VERSION 5.7 ;
  NOWIREEXTENSIONATPIN ON ;
  DIVIDERCHAR "/" ;
  BUSBITCHARS "[]" ;
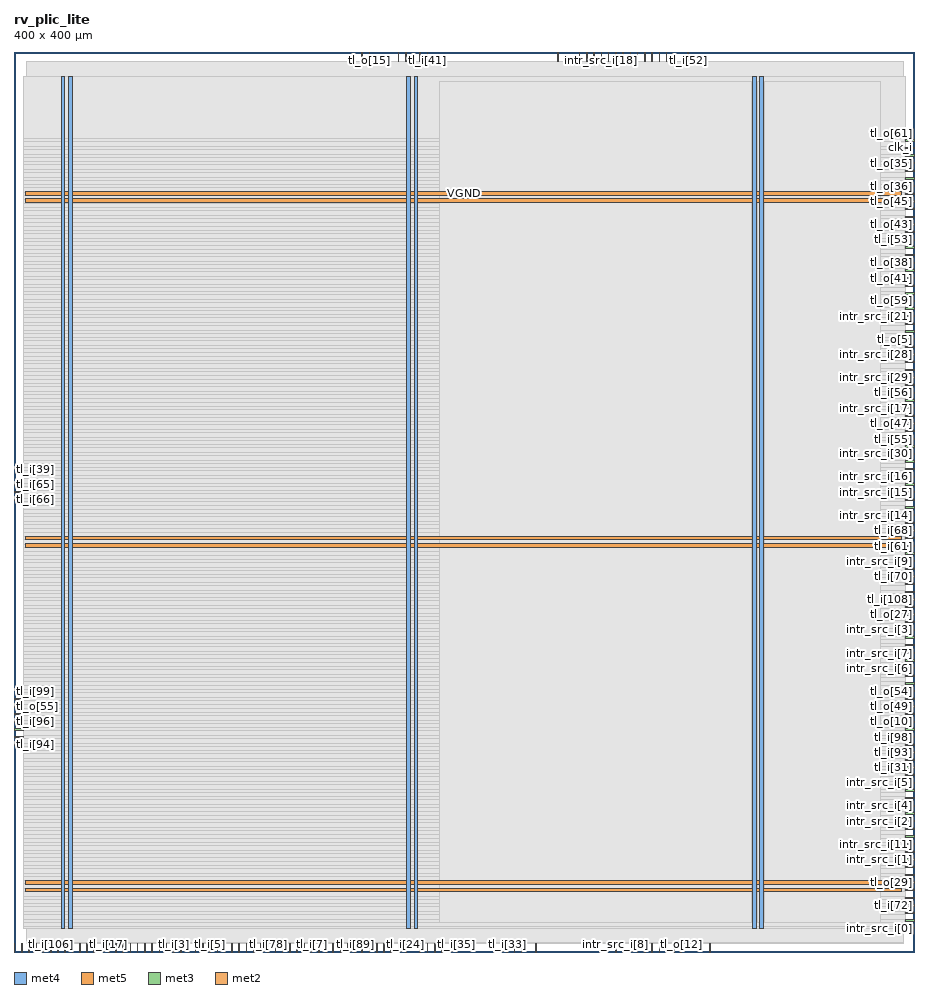
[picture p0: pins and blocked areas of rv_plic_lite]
MACRO rv_plic_lite
  CLASS BLOCK ;
  FOREIGN rv_plic_lite ;
  ORIGIN 0.000 0.000 ;
  SIZE 400.000 BY 400.000 ;
  PIN VGND
    DIRECTION INOUT ;
    USE GROUND ;
    PORT
      LAYER met4 ;
        RECT 24.340 10.640 25.940 389.200 ;
    END
    PORT
      LAYER met4 ;
        RECT 177.940 10.640 179.540 389.200 ;
    END
    PORT
      LAYER met4 ;
        RECT 331.540 10.640 333.140 389.200 ;
    END
    PORT
      LAYER met5 ;
        RECT 5.280 30.030 394.460 31.630 ;
    END
    PORT
      LAYER met5 ;
        RECT 5.280 183.210 394.460 184.810 ;
    END
    PORT
      LAYER met5 ;
        RECT 5.280 336.390 394.460 337.990 ;
    END
  END VGND
  PIN VPWR
    DIRECTION INOUT ;
    USE POWER ;
    PORT
      LAYER met4 ;
        RECT 21.040 10.640 22.640 389.200 ;
    END
    PORT
      LAYER met4 ;
        RECT 174.640 10.640 176.240 389.200 ;
    END
    PORT
      LAYER met4 ;
        RECT 328.240 10.640 329.840 389.200 ;
    END
    PORT
      LAYER met5 ;
        RECT 5.280 26.730 394.460 28.330 ;
    END
    PORT
      LAYER met5 ;
        RECT 5.280 179.910 394.460 181.510 ;
    END
    PORT
      LAYER met5 ;
        RECT 5.280 333.090 394.460 334.690 ;
    END
  END VPWR
  PIN clk_i
    DIRECTION INPUT ;
    USE SIGNAL ;
    ANTENNAGATEAREA 1.286700 ;
    ANTENNADIFFAREA 0.434700 ;
    PORT
      LAYER met3 ;
        RECT 396.000 357.040 400.000 357.640 ;
    END
  END clk_i
  PIN intr_src_i[0]
    DIRECTION INPUT ;
    USE SIGNAL ;
    ANTENNAGATEAREA 0.682200 ;
    ANTENNADIFFAREA 0.434700 ;
    PORT
      LAYER met3 ;
        RECT 396.000 10.240 400.000 10.840 ;
    END
  END intr_src_i[0]
  PIN intr_src_i[10]
    DIRECTION INPUT ;
    USE SIGNAL ;
    ANTENNAGATEAREA 0.631200 ;
    ANTENNADIFFAREA 0.434700 ;
    PORT
      LAYER met3 ;
        RECT 396.000 61.240 400.000 61.840 ;
    END
  END intr_src_i[10]
  PIN intr_src_i[11]
    DIRECTION INPUT ;
    USE SIGNAL ;
    ANTENNAGATEAREA 0.631200 ;
    ANTENNADIFFAREA 0.434700 ;
    PORT
      LAYER met3 ;
        RECT 396.000 44.240 400.000 44.840 ;
    END
  END intr_src_i[11]
  PIN intr_src_i[12]
    DIRECTION INPUT ;
    USE SIGNAL ;
    ANTENNAGATEAREA 0.631200 ;
    ANTENNADIFFAREA 0.434700 ;
    PORT
      LAYER met3 ;
        RECT 396.000 166.640 400.000 167.240 ;
    END
  END intr_src_i[12]
  PIN intr_src_i[13]
    DIRECTION INPUT ;
    USE SIGNAL ;
    ANTENNAGATEAREA 0.631200 ;
    ANTENNADIFFAREA 0.434700 ;
    PORT
      LAYER met3 ;
        RECT 396.000 183.640 400.000 184.240 ;
    END
  END intr_src_i[13]
  PIN intr_src_i[14]
    DIRECTION INPUT ;
    USE SIGNAL ;
    ANTENNAGATEAREA 0.631200 ;
    ANTENNADIFFAREA 0.434700 ;
    PORT
      LAYER met3 ;
        RECT 396.000 193.840 400.000 194.440 ;
    END
  END intr_src_i[14]
  PIN intr_src_i[15]
    DIRECTION INPUT ;
    USE SIGNAL ;
    ANTENNAGATEAREA 0.631200 ;
    ANTENNADIFFAREA 0.434700 ;
    PORT
      LAYER met3 ;
        RECT 396.000 204.040 400.000 204.640 ;
    END
  END intr_src_i[15]
  PIN intr_src_i[16]
    DIRECTION INPUT ;
    USE SIGNAL ;
    ANTENNAGATEAREA 0.631200 ;
    ANTENNADIFFAREA 0.434700 ;
    PORT
      LAYER met3 ;
        RECT 396.000 210.840 400.000 211.440 ;
    END
  END intr_src_i[16]
  PIN intr_src_i[17]
    DIRECTION INPUT ;
    USE SIGNAL ;
    ANTENNAGATEAREA 0.631200 ;
    ANTENNADIFFAREA 0.434700 ;
    PORT
      LAYER met3 ;
        RECT 396.000 241.440 400.000 242.040 ;
    END
  END intr_src_i[17]
  PIN intr_src_i[18]
    DIRECTION INPUT ;
    USE SIGNAL ;
    ANTENNAGATEAREA 0.631200 ;
    ANTENNADIFFAREA 0.434700 ;
    PORT
      LAYER met2 ;
        RECT 260.910 396.000 261.190 400.000 ;
    END
  END intr_src_i[18]
  PIN intr_src_i[19]
    DIRECTION INPUT ;
    USE SIGNAL ;
    ANTENNAGATEAREA 0.631200 ;
    ANTENNADIFFAREA 0.434700 ;
    PORT
      LAYER met3 ;
        RECT 396.000 346.840 400.000 347.440 ;
    END
  END intr_src_i[19]
  PIN intr_src_i[1]
    DIRECTION INPUT ;
    USE SIGNAL ;
    ANTENNAGATEAREA 0.647700 ;
    ANTENNADIFFAREA 0.434700 ;
    PORT
      LAYER met3 ;
        RECT 396.000 40.840 400.000 41.440 ;
    END
  END intr_src_i[1]
  PIN intr_src_i[20]
    DIRECTION INPUT ;
    USE SIGNAL ;
    ANTENNAGATEAREA 0.631200 ;
    ANTENNADIFFAREA 0.434700 ;
    PORT
      LAYER met2 ;
        RECT 270.570 396.000 270.850 400.000 ;
    END
  END intr_src_i[20]
  PIN intr_src_i[21]
    DIRECTION INPUT ;
    USE SIGNAL ;
    ANTENNAGATEAREA 0.631200 ;
    ANTENNADIFFAREA 0.434700 ;
    PORT
      LAYER met3 ;
        RECT 396.000 282.240 400.000 282.840 ;
    END
  END intr_src_i[21]
  PIN intr_src_i[22]
    DIRECTION INPUT ;
    USE SIGNAL ;
    ANTENNAGATEAREA 0.631200 ;
    ANTENNADIFFAREA 0.434700 ;
    PORT
      LAYER met2 ;
        RECT 280.230 396.000 280.510 400.000 ;
    END
  END intr_src_i[22]
  PIN intr_src_i[23]
    DIRECTION INPUT ;
    USE SIGNAL ;
    ANTENNAGATEAREA 0.631200 ;
    ANTENNADIFFAREA 0.434700 ;
    PORT
      LAYER met2 ;
        RECT 283.450 396.000 283.730 400.000 ;
    END
  END intr_src_i[23]
  PIN intr_src_i[24]
    DIRECTION INPUT ;
    USE SIGNAL ;
    ANTENNAGATEAREA 0.631200 ;
    ANTENNADIFFAREA 0.434700 ;
    PORT
      LAYER met3 ;
        RECT 396.000 329.840 400.000 330.440 ;
    END
  END intr_src_i[24]
  PIN intr_src_i[25]
    DIRECTION INPUT ;
    USE SIGNAL ;
    ANTENNAGATEAREA 0.631200 ;
    ANTENNADIFFAREA 0.434700 ;
    PORT
      LAYER met3 ;
        RECT 396.000 319.640 400.000 320.240 ;
    END
  END intr_src_i[25]
  PIN intr_src_i[26]
    DIRECTION INPUT ;
    USE SIGNAL ;
    ANTENNAGATEAREA 0.631200 ;
    ANTENNADIFFAREA 0.434700 ;
    PORT
      LAYER met2 ;
        RECT 264.130 396.000 264.410 400.000 ;
    END
  END intr_src_i[26]
  PIN intr_src_i[27]
    DIRECTION INPUT ;
    USE SIGNAL ;
    ANTENNAGATEAREA 0.631200 ;
    ANTENNADIFFAREA 0.434700 ;
    PORT
      LAYER met3 ;
        RECT 396.000 278.840 400.000 279.440 ;
    END
  END intr_src_i[27]
  PIN intr_src_i[28]
    DIRECTION INPUT ;
    USE SIGNAL ;
    ANTENNAGATEAREA 0.631200 ;
    ANTENNADIFFAREA 0.434700 ;
    PORT
      LAYER met3 ;
        RECT 396.000 265.240 400.000 265.840 ;
    END
  END intr_src_i[28]
  PIN intr_src_i[29]
    DIRECTION INPUT ;
    USE SIGNAL ;
    ANTENNAGATEAREA 0.631200 ;
    ANTENNADIFFAREA 0.434700 ;
    PORT
      LAYER met3 ;
        RECT 396.000 255.040 400.000 255.640 ;
    END
  END intr_src_i[29]
  PIN intr_src_i[2]
    DIRECTION INPUT ;
    USE SIGNAL ;
    ANTENNAGATEAREA 0.631200 ;
    ANTENNADIFFAREA 0.434700 ;
    PORT
      LAYER met3 ;
        RECT 396.000 57.840 400.000 58.440 ;
    END
  END intr_src_i[2]
  PIN intr_src_i[30]
    DIRECTION INPUT ;
    USE SIGNAL ;
    ANTENNAGATEAREA 0.631200 ;
    ANTENNADIFFAREA 0.434700 ;
    PORT
      LAYER met3 ;
        RECT 396.000 221.040 400.000 221.640 ;
    END
  END intr_src_i[30]
  PIN intr_src_i[31]
    DIRECTION INPUT ;
    USE SIGNAL ;
    ANTENNAGATEAREA 0.631200 ;
    ANTENNADIFFAREA 0.434700 ;
    PORT
      LAYER met3 ;
        RECT 396.000 285.640 400.000 286.240 ;
    END
  END intr_src_i[31]
  PIN intr_src_i[3]
    DIRECTION INPUT ;
    USE SIGNAL ;
    ANTENNAGATEAREA 0.631200 ;
    ANTENNADIFFAREA 0.434700 ;
    PORT
      LAYER met3 ;
        RECT 396.000 142.840 400.000 143.440 ;
    END
  END intr_src_i[3]
  PIN intr_src_i[4]
    DIRECTION INPUT ;
    USE SIGNAL ;
    ANTENNAGATEAREA 0.631200 ;
    ANTENNADIFFAREA 0.434700 ;
    PORT
      LAYER met3 ;
        RECT 396.000 64.640 400.000 65.240 ;
    END
  END intr_src_i[4]
  PIN intr_src_i[5]
    DIRECTION INPUT ;
    USE SIGNAL ;
    ANTENNAGATEAREA 0.631200 ;
    ANTENNADIFFAREA 0.434700 ;
    PORT
      LAYER met3 ;
        RECT 396.000 74.840 400.000 75.440 ;
    END
  END intr_src_i[5]
  PIN intr_src_i[6]
    DIRECTION INPUT ;
    USE SIGNAL ;
    ANTENNAGATEAREA 0.631200 ;
    ANTENNADIFFAREA 0.434700 ;
    PORT
      LAYER met3 ;
        RECT 396.000 125.840 400.000 126.440 ;
    END
  END intr_src_i[6]
  PIN intr_src_i[7]
    DIRECTION INPUT ;
    USE SIGNAL ;
    ANTENNAGATEAREA 0.631200 ;
    ANTENNADIFFAREA 0.434700 ;
    PORT
      LAYER met3 ;
        RECT 396.000 129.240 400.000 129.840 ;
    END
  END intr_src_i[7]
  PIN intr_src_i[8]
    DIRECTION INPUT ;
    USE SIGNAL ;
    ANTENNAGATEAREA 0.560700 ;
    ANTENNADIFFAREA 0.434700 ;
    PORT
      LAYER met2 ;
        RECT 267.350 0.000 267.630 4.000 ;
    END
  END intr_src_i[8]
  PIN intr_src_i[9]
    DIRECTION INPUT ;
    USE SIGNAL ;
    ANTENNAGATEAREA 0.631200 ;
    ANTENNADIFFAREA 0.434700 ;
    PORT
      LAYER met3 ;
        RECT 396.000 173.440 400.000 174.040 ;
    END
  END intr_src_i[9]
  PIN irq_o
    DIRECTION OUTPUT ;
    USE SIGNAL ;
    ANTENNADIFFAREA 1.336500 ;
    PORT
      LAYER met3 ;
        RECT 396.000 27.240 400.000 27.840 ;
    END
  END irq_o
  PIN rst_ni
    DIRECTION INPUT ;
    USE SIGNAL ;
    ANTENNAGATEAREA 0.647700 ;
    ANTENNADIFFAREA 0.434700 ;
    PORT
      LAYER met3 ;
        RECT 396.000 312.840 400.000 313.440 ;
    END
  END rst_ni
  PIN tl_i[0]
    DIRECTION INPUT ;
    USE SIGNAL ;
    PORT
      LAYER met2 ;
        RECT 3.310 0.000 3.590 4.000 ;
    END
  END tl_i[0]
  PIN tl_i[100]
    DIRECTION INPUT ;
    USE SIGNAL ;
    ANTENNAGATEAREA 0.631200 ;
    ANTENNADIFFAREA 0.434700 ;
    PORT
      LAYER met3 ;
        RECT 396.000 78.240 400.000 78.840 ;
    END
  END tl_i[100]
  PIN tl_i[101]
    DIRECTION INPUT ;
    USE SIGNAL ;
    ANTENNAGATEAREA 0.631200 ;
    ANTENNADIFFAREA 0.434700 ;
    PORT
      LAYER met2 ;
        RECT 289.890 0.000 290.170 4.000 ;
    END
  END tl_i[101]
  PIN tl_i[102]
    DIRECTION INPUT ;
    USE SIGNAL ;
    ANTENNAGATEAREA 0.631200 ;
    ANTENNADIFFAREA 0.434700 ;
    PORT
      LAYER met2 ;
        RECT 270.570 0.000 270.850 4.000 ;
    END
  END tl_i[102]
  PIN tl_i[103]
    DIRECTION INPUT ;
    USE SIGNAL ;
    PORT
      LAYER met2 ;
        RECT 6.530 0.000 6.810 4.000 ;
    END
  END tl_i[103]
  PIN tl_i[104]
    DIRECTION INPUT ;
    USE SIGNAL ;
    PORT
      LAYER met2 ;
        RECT 9.750 0.000 10.030 4.000 ;
    END
  END tl_i[104]
  PIN tl_i[105]
    DIRECTION INPUT ;
    USE SIGNAL ;
    PORT
      LAYER met2 ;
        RECT 12.970 0.000 13.250 4.000 ;
    END
  END tl_i[105]
  PIN tl_i[106]
    DIRECTION INPUT ;
    USE SIGNAL ;
    PORT
      LAYER met2 ;
        RECT 16.190 0.000 16.470 4.000 ;
    END
  END tl_i[106]
  PIN tl_i[107]
    DIRECTION INPUT ;
    USE SIGNAL ;
    ANTENNAGATEAREA 0.593700 ;
    ANTENNADIFFAREA 0.434700 ;
    PORT
      LAYER met3 ;
        RECT 396.000 37.440 400.000 38.040 ;
    END
  END tl_i[107]
  PIN tl_i[108]
    DIRECTION INPUT ;
    USE SIGNAL ;
    ANTENNAGATEAREA 0.647700 ;
    ANTENNADIFFAREA 0.434700 ;
    PORT
      LAYER met3 ;
        RECT 396.000 156.440 400.000 157.040 ;
    END
  END tl_i[108]
  PIN tl_i[109]
    DIRECTION INPUT ;
    USE SIGNAL ;
    ANTENNAGATEAREA 0.647700 ;
    ANTENNADIFFAREA 0.434700 ;
    PORT
      LAYER met3 ;
        RECT 396.000 326.440 400.000 327.040 ;
    END
  END tl_i[109]
  PIN tl_i[10]
    DIRECTION INPUT ;
    USE SIGNAL ;
    PORT
      LAYER met2 ;
        RECT 19.410 0.000 19.690 4.000 ;
    END
  END tl_i[10]
  PIN tl_i[11]
    DIRECTION INPUT ;
    USE SIGNAL ;
    PORT
      LAYER met2 ;
        RECT 22.630 0.000 22.910 4.000 ;
    END
  END tl_i[11]
  PIN tl_i[12]
    DIRECTION INPUT ;
    USE SIGNAL ;
    PORT
      LAYER met2 ;
        RECT 25.850 0.000 26.130 4.000 ;
    END
  END tl_i[12]
  PIN tl_i[13]
    DIRECTION INPUT ;
    USE SIGNAL ;
    PORT
      LAYER met2 ;
        RECT 29.070 0.000 29.350 4.000 ;
    END
  END tl_i[13]
  PIN tl_i[14]
    DIRECTION INPUT ;
    USE SIGNAL ;
    PORT
      LAYER met2 ;
        RECT 32.290 0.000 32.570 4.000 ;
    END
  END tl_i[14]
  PIN tl_i[15]
    DIRECTION INPUT ;
    USE SIGNAL ;
    PORT
      LAYER met2 ;
        RECT 35.510 0.000 35.790 4.000 ;
    END
  END tl_i[15]
  PIN tl_i[16]
    DIRECTION INPUT ;
    USE SIGNAL ;
    PORT
      LAYER met2 ;
        RECT 38.730 0.000 39.010 4.000 ;
    END
  END tl_i[16]
  PIN tl_i[17]
    DIRECTION INPUT ;
    USE SIGNAL ;
    PORT
      LAYER met2 ;
        RECT 41.950 0.000 42.230 4.000 ;
    END
  END tl_i[17]
  PIN tl_i[18]
    DIRECTION INPUT ;
    USE SIGNAL ;
    PORT
      LAYER met2 ;
        RECT 45.170 0.000 45.450 4.000 ;
    END
  END tl_i[18]
  PIN tl_i[19]
    DIRECTION INPUT ;
    USE SIGNAL ;
    PORT
      LAYER met2 ;
        RECT 48.390 0.000 48.670 4.000 ;
    END
  END tl_i[19]
  PIN tl_i[1]
    DIRECTION INPUT ;
    USE SIGNAL ;
    PORT
      LAYER met2 ;
        RECT 51.610 0.000 51.890 4.000 ;
    END
  END tl_i[1]
  PIN tl_i[20]
    DIRECTION INPUT ;
    USE SIGNAL ;
    PORT
      LAYER met2 ;
        RECT 54.830 0.000 55.110 4.000 ;
    END
  END tl_i[20]
  PIN tl_i[21]
    DIRECTION INPUT ;
    USE SIGNAL ;
    PORT
      LAYER met2 ;
        RECT 58.050 0.000 58.330 4.000 ;
    END
  END tl_i[21]
  PIN tl_i[22]
    DIRECTION INPUT ;
    USE SIGNAL ;
    PORT
      LAYER met2 ;
        RECT 61.270 0.000 61.550 4.000 ;
    END
  END tl_i[22]
  PIN tl_i[23]
    DIRECTION INPUT ;
    USE SIGNAL ;
    PORT
      LAYER met2 ;
        RECT 64.490 0.000 64.770 4.000 ;
    END
  END tl_i[23]
  PIN tl_i[24]
    DIRECTION INPUT ;
    USE SIGNAL ;
    PORT
      LAYER met2 ;
        RECT 173.970 0.000 174.250 4.000 ;
    END
  END tl_i[24]
  PIN tl_i[25]
    DIRECTION INPUT ;
    USE SIGNAL ;
    ANTENNAGATEAREA 0.631200 ;
    ANTENNADIFFAREA 0.434700 ;
    PORT
      LAYER met2 ;
        RECT 251.250 396.000 251.530 400.000 ;
    END
  END tl_i[25]
  PIN tl_i[26]
    DIRECTION INPUT ;
    USE SIGNAL ;
    ANTENNAGATEAREA 0.631200 ;
    ANTENNADIFFAREA 0.434700 ;
    PORT
      LAYER met2 ;
        RECT 254.470 396.000 254.750 400.000 ;
    END
  END tl_i[26]
  PIN tl_i[27]
    DIRECTION INPUT ;
    USE SIGNAL ;
    ANTENNAGATEAREA 0.631200 ;
    ANTENNADIFFAREA 0.434700 ;
    PORT
      LAYER met2 ;
        RECT 241.590 396.000 241.870 400.000 ;
    END
  END tl_i[27]
  PIN tl_i[28]
    DIRECTION INPUT ;
    USE SIGNAL ;
    ANTENNAGATEAREA 0.631200 ;
    ANTENNADIFFAREA 0.434700 ;
    PORT
      LAYER met3 ;
        RECT 396.000 51.040 400.000 51.640 ;
    END
  END tl_i[28]
  PIN tl_i[29]
    DIRECTION INPUT ;
    USE SIGNAL ;
    ANTENNAGATEAREA 0.631200 ;
    ANTENNADIFFAREA 0.434700 ;
    PORT
      LAYER met2 ;
        RECT 273.790 0.000 274.070 4.000 ;
    END
  END tl_i[29]
  PIN tl_i[2]
    DIRECTION INPUT ;
    USE SIGNAL ;
    PORT
      LAYER met2 ;
        RECT 67.710 0.000 67.990 4.000 ;
    END
  END tl_i[2]
  PIN tl_i[30]
    DIRECTION INPUT ;
    USE SIGNAL ;
    ANTENNAGATEAREA 0.631200 ;
    ANTENNADIFFAREA 0.434700 ;
    PORT
      LAYER met3 ;
        RECT 396.000 122.440 400.000 123.040 ;
    END
  END tl_i[30]
  PIN tl_i[31]
    DIRECTION INPUT ;
    USE SIGNAL ;
    ANTENNAGATEAREA 0.631200 ;
    ANTENNADIFFAREA 0.434700 ;
    PORT
      LAYER met3 ;
        RECT 396.000 81.640 400.000 82.240 ;
    END
  END tl_i[31]
  PIN tl_i[32]
    DIRECTION INPUT ;
    USE SIGNAL ;
    ANTENNAGATEAREA 0.631200 ;
    ANTENNADIFFAREA 0.434700 ;
    PORT
      LAYER met2 ;
        RECT 183.630 0.000 183.910 4.000 ;
    END
  END tl_i[32]
  PIN tl_i[33]
    DIRECTION INPUT ;
    USE SIGNAL ;
    ANTENNAGATEAREA 0.631200 ;
    ANTENNADIFFAREA 0.434700 ;
    PORT
      LAYER met2 ;
        RECT 219.050 0.000 219.330 4.000 ;
    END
  END tl_i[33]
  PIN tl_i[34]
    DIRECTION INPUT ;
    USE SIGNAL ;
    ANTENNAGATEAREA 0.631200 ;
    ANTENNADIFFAREA 0.434700 ;
    PORT
      LAYER met2 ;
        RECT 225.490 0.000 225.770 4.000 ;
    END
  END tl_i[34]
  PIN tl_i[35]
    DIRECTION INPUT ;
    USE SIGNAL ;
    ANTENNAGATEAREA 0.631200 ;
    ANTENNADIFFAREA 0.434700 ;
    PORT
      LAYER met2 ;
        RECT 196.510 0.000 196.790 4.000 ;
    END
  END tl_i[35]
  PIN tl_i[36]
    DIRECTION INPUT ;
    USE SIGNAL ;
    ANTENNAGATEAREA 0.631200 ;
    ANTENNADIFFAREA 0.434700 ;
    PORT
      LAYER met3 ;
        RECT 396.000 136.040 400.000 136.640 ;
    END
  END tl_i[36]
  PIN tl_i[37]
    DIRECTION INPUT ;
    USE SIGNAL ;
    ANTENNAGATEAREA 0.631200 ;
    ANTENNADIFFAREA 0.434700 ;
    PORT
      LAYER met2 ;
        RECT 180.410 0.000 180.690 4.000 ;
    END
  END tl_i[37]
  PIN tl_i[38]
    DIRECTION INPUT ;
    USE SIGNAL ;
    ANTENNAGATEAREA 0.631200 ;
    ANTENNADIFFAREA 0.434700 ;
    PORT
      LAYER met2 ;
        RECT 222.270 0.000 222.550 4.000 ;
    END
  END tl_i[38]
  PIN tl_i[39]
    DIRECTION INPUT ;
    USE SIGNAL ;
    ANTENNAGATEAREA 0.631200 ;
    ANTENNADIFFAREA 0.434700 ;
    PORT
      LAYER met3 ;
        RECT 0.000 214.240 4.000 214.840 ;
    END
  END tl_i[39]
  PIN tl_i[3]
    DIRECTION INPUT ;
    USE SIGNAL ;
    PORT
      LAYER met2 ;
        RECT 70.930 0.000 71.210 4.000 ;
    END
  END tl_i[3]
  PIN tl_i[40]
    DIRECTION INPUT ;
    USE SIGNAL ;
    ANTENNAGATEAREA 0.631200 ;
    ANTENNADIFFAREA 0.434700 ;
    PORT
      LAYER met3 ;
        RECT 396.000 207.440 400.000 208.040 ;
    END
  END tl_i[40]
  PIN tl_i[41]
    DIRECTION INPUT ;
    USE SIGNAL ;
    ANTENNAGATEAREA 0.631200 ;
    ANTENNADIFFAREA 0.434700 ;
    PORT
      LAYER met2 ;
        RECT 183.630 396.000 183.910 400.000 ;
    END
  END tl_i[41]
  PIN tl_i[42]
    DIRECTION INPUT ;
    USE SIGNAL ;
    ANTENNAGATEAREA 0.631200 ;
    ANTENNADIFFAREA 0.434700 ;
    PORT
      LAYER met2 ;
        RECT 173.970 396.000 174.250 400.000 ;
    END
  END tl_i[42]
  PIN tl_i[43]
    DIRECTION INPUT ;
    USE SIGNAL ;
    ANTENNAGATEAREA 0.631200 ;
    ANTENNADIFFAREA 0.434700 ;
    PORT
      LAYER met2 ;
        RECT 170.750 396.000 171.030 400.000 ;
    END
  END tl_i[43]
  PIN tl_i[44]
    DIRECTION INPUT ;
    USE SIGNAL ;
    ANTENNAGATEAREA 0.631200 ;
    ANTENNADIFFAREA 0.434700 ;
    PORT
      LAYER met2 ;
        RECT 180.410 396.000 180.690 400.000 ;
    END
  END tl_i[44]
  PIN tl_i[45]
    DIRECTION INPUT ;
    USE SIGNAL ;
    ANTENNAGATEAREA 0.631200 ;
    ANTENNADIFFAREA 0.434700 ;
    PORT
      LAYER met2 ;
        RECT 267.350 396.000 267.630 400.000 ;
    END
  END tl_i[45]
  PIN tl_i[46]
    DIRECTION INPUT ;
    USE SIGNAL ;
    ANTENNAGATEAREA 0.631200 ;
    ANTENNADIFFAREA 0.434700 ;
    PORT
      LAYER met3 ;
        RECT 396.000 295.840 400.000 296.440 ;
    END
  END tl_i[46]
  PIN tl_i[47]
    DIRECTION INPUT ;
    USE SIGNAL ;
    ANTENNAGATEAREA 0.631200 ;
    ANTENNADIFFAREA 0.434700 ;
    PORT
      LAYER met2 ;
        RECT 273.790 396.000 274.070 400.000 ;
    END
  END tl_i[47]
  PIN tl_i[48]
    DIRECTION INPUT ;
    USE SIGNAL ;
    ANTENNAGATEAREA 0.631200 ;
    ANTENNADIFFAREA 0.434700 ;
    PORT
      LAYER met2 ;
        RECT 289.890 396.000 290.170 400.000 ;
    END
  END tl_i[48]
  PIN tl_i[49]
    DIRECTION INPUT ;
    USE SIGNAL ;
    ANTENNAGATEAREA 0.631200 ;
    ANTENNADIFFAREA 0.434700 ;
    PORT
      LAYER met2 ;
        RECT 286.670 396.000 286.950 400.000 ;
    END
  END tl_i[49]
  PIN tl_i[4]
    DIRECTION INPUT ;
    USE SIGNAL ;
    PORT
      LAYER met2 ;
        RECT 74.150 0.000 74.430 4.000 ;
    END
  END tl_i[4]
  PIN tl_i[50]
    DIRECTION INPUT ;
    USE SIGNAL ;
    ANTENNAGATEAREA 0.631200 ;
    ANTENNADIFFAREA 0.434700 ;
    PORT
      LAYER met2 ;
        RECT 277.010 396.000 277.290 400.000 ;
    END
  END tl_i[50]
  PIN tl_i[51]
    DIRECTION INPUT ;
    USE SIGNAL ;
    ANTENNAGATEAREA 0.631200 ;
    ANTENNADIFFAREA 0.434700 ;
    PORT
      LAYER met2 ;
        RECT 257.690 396.000 257.970 400.000 ;
    END
  END tl_i[51]
  PIN tl_i[52]
    DIRECTION INPUT ;
    USE SIGNAL ;
    ANTENNAGATEAREA 0.631200 ;
    ANTENNADIFFAREA 0.434700 ;
    PORT
      LAYER met2 ;
        RECT 299.550 396.000 299.830 400.000 ;
    END
  END tl_i[52]
  PIN tl_i[53]
    DIRECTION INPUT ;
    USE SIGNAL ;
    ANTENNAGATEAREA 0.631200 ;
    ANTENNADIFFAREA 0.434700 ;
    PORT
      LAYER met3 ;
        RECT 396.000 316.240 400.000 316.840 ;
    END
  END tl_i[53]
  PIN tl_i[54]
    DIRECTION INPUT ;
    USE SIGNAL ;
    ANTENNAGATEAREA 0.631200 ;
    ANTENNADIFFAREA 0.434700 ;
    PORT
      LAYER met3 ;
        RECT 396.000 258.440 400.000 259.040 ;
    END
  END tl_i[54]
  PIN tl_i[55]
    DIRECTION INPUT ;
    USE SIGNAL ;
    ANTENNAGATEAREA 0.631200 ;
    ANTENNADIFFAREA 0.434700 ;
    PORT
      LAYER met3 ;
        RECT 396.000 224.440 400.000 225.040 ;
    END
  END tl_i[55]
  PIN tl_i[56]
    DIRECTION INPUT ;
    USE SIGNAL ;
    ANTENNAGATEAREA 0.631200 ;
    ANTENNADIFFAREA 0.434700 ;
    PORT
      LAYER met3 ;
        RECT 396.000 248.240 400.000 248.840 ;
    END
  END tl_i[56]
  PIN tl_i[57]
    DIRECTION INPUT ;
    USE SIGNAL ;
    PORT
      LAYER met2 ;
        RECT 77.370 0.000 77.650 4.000 ;
    END
  END tl_i[57]
  PIN tl_i[58]
    DIRECTION INPUT ;
    USE SIGNAL ;
    PORT
      LAYER met2 ;
        RECT 80.590 0.000 80.870 4.000 ;
    END
  END tl_i[58]
  PIN tl_i[59]
    DIRECTION INPUT ;
    USE SIGNAL ;
    PORT
      LAYER met2 ;
        RECT 83.810 0.000 84.090 4.000 ;
    END
  END tl_i[59]
  PIN tl_i[5]
    DIRECTION INPUT ;
    USE SIGNAL ;
    PORT
      LAYER met2 ;
        RECT 87.030 0.000 87.310 4.000 ;
    END
  END tl_i[5]
  PIN tl_i[60]
    DIRECTION INPUT ;
    USE SIGNAL ;
    PORT
      LAYER met2 ;
        RECT 90.250 0.000 90.530 4.000 ;
    END
  END tl_i[60]
  PIN tl_i[61]
    DIRECTION INPUT ;
    USE SIGNAL ;
    ANTENNAGATEAREA 0.631200 ;
    ANTENNADIFFAREA 0.434700 ;
    PORT
      LAYER met3 ;
        RECT 396.000 176.840 400.000 177.440 ;
    END
  END tl_i[61]
  PIN tl_i[62]
    DIRECTION INPUT ;
    USE SIGNAL ;
    ANTENNAGATEAREA 0.631200 ;
    ANTENNADIFFAREA 0.434700 ;
    PORT
      LAYER met3 ;
        RECT 396.000 180.240 400.000 180.840 ;
    END
  END tl_i[62]
  PIN tl_i[63]
    DIRECTION INPUT ;
    USE SIGNAL ;
    ANTENNAGATEAREA 0.647700 ;
    ANTENNADIFFAREA 0.434700 ;
    PORT
      LAYER met2 ;
        RECT 190.070 0.000 190.350 4.000 ;
    END
  END tl_i[63]
  PIN tl_i[64]
    DIRECTION INPUT ;
    USE SIGNAL ;
    ANTENNAGATEAREA 0.647700 ;
    ANTENNADIFFAREA 0.434700 ;
    PORT
      LAYER met2 ;
        RECT 186.850 0.000 187.130 4.000 ;
    END
  END tl_i[64]
  PIN tl_i[65]
    DIRECTION INPUT ;
    USE SIGNAL ;
    ANTENNAGATEAREA 0.647700 ;
    ANTENNADIFFAREA 0.434700 ;
    PORT
      LAYER met3 ;
        RECT 0.000 207.440 4.000 208.040 ;
    END
  END tl_i[65]
  PIN tl_i[66]
    DIRECTION INPUT ;
    USE SIGNAL ;
    ANTENNAGATEAREA 0.647700 ;
    ANTENNADIFFAREA 0.434700 ;
    PORT
      LAYER met3 ;
        RECT 0.000 204.040 4.000 204.640 ;
    END
  END tl_i[66]
  PIN tl_i[67]
    DIRECTION INPUT ;
    USE SIGNAL ;
    ANTENNAGATEAREA 0.647700 ;
    ANTENNADIFFAREA 0.434700 ;
    PORT
      LAYER met3 ;
        RECT 0.000 200.640 4.000 201.240 ;
    END
  END tl_i[67]
  PIN tl_i[68]
    DIRECTION INPUT ;
    USE SIGNAL ;
    ANTENNAGATEAREA 0.647700 ;
    ANTENNADIFFAREA 0.434700 ;
    PORT
      LAYER met3 ;
        RECT 396.000 187.040 400.000 187.640 ;
    END
  END tl_i[68]
  PIN tl_i[69]
    DIRECTION INPUT ;
    USE SIGNAL ;
    ANTENNAGATEAREA 0.593700 ;
    ANTENNADIFFAREA 0.434700 ;
    PORT
      LAYER met3 ;
        RECT 396.000 17.040 400.000 17.640 ;
    END
  END tl_i[69]
  PIN tl_i[6]
    DIRECTION INPUT ;
    USE SIGNAL ;
    PORT
      LAYER met2 ;
        RECT 93.470 0.000 93.750 4.000 ;
    END
  END tl_i[6]
  PIN tl_i[70]
    DIRECTION INPUT ;
    USE SIGNAL ;
    ANTENNAGATEAREA 0.631200 ;
    ANTENNADIFFAREA 0.434700 ;
    PORT
      LAYER met3 ;
        RECT 396.000 170.040 400.000 170.640 ;
    END
  END tl_i[70]
  PIN tl_i[71]
    DIRECTION INPUT ;
    USE SIGNAL ;
    ANTENNAGATEAREA 0.593700 ;
    ANTENNADIFFAREA 0.434700 ;
    PORT
      LAYER met3 ;
        RECT 396.000 23.840 400.000 24.440 ;
    END
  END tl_i[71]
  PIN tl_i[72]
    DIRECTION INPUT ;
    USE SIGNAL ;
    ANTENNAGATEAREA 0.593700 ;
    ANTENNADIFFAREA 0.434700 ;
    PORT
      LAYER met3 ;
        RECT 396.000 20.440 400.000 21.040 ;
    END
  END tl_i[72]
  PIN tl_i[73]
    DIRECTION INPUT ;
    USE SIGNAL ;
    PORT
      LAYER met2 ;
        RECT 96.690 0.000 96.970 4.000 ;
    END
  END tl_i[73]
  PIN tl_i[74]
    DIRECTION INPUT ;
    USE SIGNAL ;
    PORT
      LAYER met2 ;
        RECT 109.570 0.000 109.850 4.000 ;
    END
  END tl_i[74]
  PIN tl_i[75]
    DIRECTION INPUT ;
    USE SIGNAL ;
    PORT
      LAYER met2 ;
        RECT 103.130 0.000 103.410 4.000 ;
    END
  END tl_i[75]
  PIN tl_i[76]
    DIRECTION INPUT ;
    USE SIGNAL ;
    PORT
      LAYER met2 ;
        RECT 106.350 0.000 106.630 4.000 ;
    END
  END tl_i[76]
  PIN tl_i[77]
    DIRECTION INPUT ;
    USE SIGNAL ;
    PORT
      LAYER met2 ;
        RECT 119.230 0.000 119.510 4.000 ;
    END
  END tl_i[77]
  PIN tl_i[78]
    DIRECTION INPUT ;
    USE SIGNAL ;
    PORT
      LAYER met2 ;
        RECT 112.790 0.000 113.070 4.000 ;
    END
  END tl_i[78]
  PIN tl_i[79]
    DIRECTION INPUT ;
    USE SIGNAL ;
    PORT
      LAYER met2 ;
        RECT 116.010 0.000 116.290 4.000 ;
    END
  END tl_i[79]
  PIN tl_i[7]
    DIRECTION INPUT ;
    USE SIGNAL ;
    PORT
      LAYER met2 ;
        RECT 132.110 0.000 132.390 4.000 ;
    END
  END tl_i[7]
  PIN tl_i[80]
    DIRECTION INPUT ;
    USE SIGNAL ;
    PORT
      LAYER met2 ;
        RECT 122.450 0.000 122.730 4.000 ;
    END
  END tl_i[80]
  PIN tl_i[81]
    DIRECTION INPUT ;
    USE SIGNAL ;
    PORT
      LAYER met2 ;
        RECT 125.670 0.000 125.950 4.000 ;
    END
  END tl_i[81]
  PIN tl_i[82]
    DIRECTION INPUT ;
    USE SIGNAL ;
    PORT
      LAYER met2 ;
        RECT 0.090 0.000 0.370 4.000 ;
    END
  END tl_i[82]
  PIN tl_i[83]
    DIRECTION INPUT ;
    USE SIGNAL ;
    PORT
      LAYER met2 ;
        RECT 144.990 0.000 145.270 4.000 ;
    END
  END tl_i[83]
  PIN tl_i[84]
    DIRECTION INPUT ;
    USE SIGNAL ;
    PORT
      LAYER met2 ;
        RECT 135.330 0.000 135.610 4.000 ;
    END
  END tl_i[84]
  PIN tl_i[85]
    DIRECTION INPUT ;
    USE SIGNAL ;
    PORT
      LAYER met2 ;
        RECT 138.550 0.000 138.830 4.000 ;
    END
  END tl_i[85]
  PIN tl_i[86]
    DIRECTION INPUT ;
    USE SIGNAL ;
    PORT
      LAYER met2 ;
        RECT 141.770 0.000 142.050 4.000 ;
    END
  END tl_i[86]
  PIN tl_i[87]
    DIRECTION INPUT ;
    USE SIGNAL ;
    PORT
      LAYER met2 ;
        RECT 157.870 0.000 158.150 4.000 ;
    END
  END tl_i[87]
  PIN tl_i[88]
    DIRECTION INPUT ;
    USE SIGNAL ;
    PORT
      LAYER met2 ;
        RECT 148.210 0.000 148.490 4.000 ;
    END
  END tl_i[88]
  PIN tl_i[89]
    DIRECTION INPUT ;
    USE SIGNAL ;
    PORT
      LAYER met2 ;
        RECT 151.430 0.000 151.710 4.000 ;
    END
  END tl_i[89]
  PIN tl_i[8]
    DIRECTION INPUT ;
    USE SIGNAL ;
    PORT
      LAYER met2 ;
        RECT 154.650 0.000 154.930 4.000 ;
    END
  END tl_i[8]
  PIN tl_i[90]
    DIRECTION INPUT ;
    USE SIGNAL ;
    PORT
      LAYER met2 ;
        RECT 170.750 0.000 171.030 4.000 ;
    END
  END tl_i[90]
  PIN tl_i[91]
    DIRECTION INPUT ;
    USE SIGNAL ;
    PORT
      LAYER met2 ;
        RECT 161.090 0.000 161.370 4.000 ;
    END
  END tl_i[91]
  PIN tl_i[92]
    DIRECTION INPUT ;
    USE SIGNAL ;
    PORT
      LAYER met2 ;
        RECT 164.310 0.000 164.590 4.000 ;
    END
  END tl_i[92]
  PIN tl_i[93]
    DIRECTION INPUT ;
    USE SIGNAL ;
    ANTENNAGATEAREA 0.631200 ;
    ANTENNADIFFAREA 0.434700 ;
    PORT
      LAYER met3 ;
        RECT 396.000 85.040 400.000 85.640 ;
    END
  END tl_i[93]
  PIN tl_i[94]
    DIRECTION INPUT ;
    USE SIGNAL ;
    ANTENNAGATEAREA 0.631200 ;
    ANTENNADIFFAREA 0.434700 ;
    PORT
      LAYER met3 ;
        RECT 0.000 91.840 4.000 92.440 ;
    END
  END tl_i[94]
  PIN tl_i[95]
    DIRECTION INPUT ;
    USE SIGNAL ;
    ANTENNAGATEAREA 0.631200 ;
    ANTENNADIFFAREA 0.434700 ;
    PORT
      LAYER met3 ;
        RECT 0.000 105.440 4.000 106.040 ;
    END
  END tl_i[95]
  PIN tl_i[96]
    DIRECTION INPUT ;
    USE SIGNAL ;
    ANTENNAGATEAREA 0.631200 ;
    ANTENNADIFFAREA 0.434700 ;
    PORT
      LAYER met3 ;
        RECT 0.000 102.040 4.000 102.640 ;
    END
  END tl_i[96]
  PIN tl_i[97]
    DIRECTION INPUT ;
    USE SIGNAL ;
    ANTENNAGATEAREA 0.631200 ;
    ANTENNADIFFAREA 0.434700 ;
    PORT
      LAYER met3 ;
        RECT 396.000 95.240 400.000 95.840 ;
    END
  END tl_i[97]
  PIN tl_i[98]
    DIRECTION INPUT ;
    USE SIGNAL ;
    ANTENNAGATEAREA 0.631200 ;
    ANTENNADIFFAREA 0.434700 ;
    PORT
      LAYER met3 ;
        RECT 396.000 91.840 400.000 92.440 ;
    END
  END tl_i[98]
  PIN tl_i[99]
    DIRECTION INPUT ;
    USE SIGNAL ;
    ANTENNAGATEAREA 0.631200 ;
    ANTENNADIFFAREA 0.434700 ;
    PORT
      LAYER met3 ;
        RECT 0.000 112.240 4.000 112.840 ;
    END
  END tl_i[99]
  PIN tl_i[9]
    DIRECTION INPUT ;
    USE SIGNAL ;
    PORT
      LAYER met2 ;
        RECT 167.530 0.000 167.810 4.000 ;
    END
  END tl_i[9]
  PIN tl_o[0]
    DIRECTION OUTPUT ;
    USE SIGNAL ;
    PORT
      LAYER met2 ;
        RECT 231.930 0.000 232.210 4.000 ;
    END
  END tl_o[0]
  PIN tl_o[10]
    DIRECTION OUTPUT ;
    USE SIGNAL ;
    ANTENNADIFFAREA 0.445500 ;
    PORT
      LAYER met3 ;
        RECT 396.000 102.040 400.000 102.640 ;
    END
  END tl_o[10]
  PIN tl_o[11]
    DIRECTION OUTPUT ;
    USE SIGNAL ;
    ANTENNADIFFAREA 0.445500 ;
    PORT
      LAYER met2 ;
        RECT 277.010 0.000 277.290 4.000 ;
    END
  END tl_o[11]
  PIN tl_o[12]
    DIRECTION OUTPUT ;
    USE SIGNAL ;
    ANTENNADIFFAREA 0.445500 ;
    PORT
      LAYER met2 ;
        RECT 296.330 0.000 296.610 4.000 ;
    END
  END tl_o[12]
  PIN tl_o[13]
    DIRECTION OUTPUT ;
    USE SIGNAL ;
    ANTENNADIFFAREA 0.445500 ;
    PORT
      LAYER met2 ;
        RECT 286.670 0.000 286.950 4.000 ;
    END
  END tl_o[13]
  PIN tl_o[14]
    DIRECTION OUTPUT ;
    USE SIGNAL ;
    ANTENNADIFFAREA 0.445500 ;
    PORT
      LAYER met3 ;
        RECT 396.000 98.640 400.000 99.240 ;
    END
  END tl_o[14]
  PIN tl_o[15]
    DIRECTION OUTPUT ;
    USE SIGNAL ;
    PORT
      LAYER met2 ;
        RECT 157.870 396.000 158.150 400.000 ;
    END
  END tl_o[15]
  PIN tl_o[16]
    DIRECTION OUTPUT ;
    USE SIGNAL ;
    ANTENNADIFFAREA 0.445500 ;
    PORT
      LAYER met3 ;
        RECT 396.000 197.240 400.000 197.840 ;
    END
  END tl_o[16]
  PIN tl_o[17]
    DIRECTION OUTPUT ;
    USE SIGNAL ;
    ANTENNADIFFAREA 0.445500 ;
    PORT
      LAYER met3 ;
        RECT 396.000 163.240 400.000 163.840 ;
    END
  END tl_o[17]
  PIN tl_o[18]
    DIRECTION OUTPUT ;
    USE SIGNAL ;
    ANTENNADIFFAREA 0.445500 ;
    PORT
      LAYER met3 ;
        RECT 396.000 13.640 400.000 14.240 ;
    END
  END tl_o[18]
  PIN tl_o[19]
    DIRECTION OUTPUT ;
    USE SIGNAL ;
    ANTENNADIFFAREA 0.445500 ;
    PORT
      LAYER met3 ;
        RECT 396.000 34.040 400.000 34.640 ;
    END
  END tl_o[19]
  PIN tl_o[1]
    DIRECTION OUTPUT ;
    USE SIGNAL ;
    ANTENNADIFFAREA 0.445500 ;
    PORT
      LAYER met2 ;
        RECT 280.230 0.000 280.510 4.000 ;
    END
  END tl_o[1]
  PIN tl_o[20]
    DIRECTION OUTPUT ;
    USE SIGNAL ;
    ANTENNADIFFAREA 0.445500 ;
    PORT
      LAYER met3 ;
        RECT 396.000 190.440 400.000 191.040 ;
    END
  END tl_o[20]
  PIN tl_o[21]
    DIRECTION OUTPUT ;
    USE SIGNAL ;
    ANTENNADIFFAREA 0.445500 ;
    PORT
      LAYER met3 ;
        RECT 396.000 71.440 400.000 72.040 ;
    END
  END tl_o[21]
  PIN tl_o[22]
    DIRECTION OUTPUT ;
    USE SIGNAL ;
    ANTENNADIFFAREA 0.445500 ;
    PORT
      LAYER met3 ;
        RECT 396.000 139.440 400.000 140.040 ;
    END
  END tl_o[22]
  PIN tl_o[23]
    DIRECTION OUTPUT ;
    USE SIGNAL ;
    ANTENNADIFFAREA 0.445500 ;
    PORT
      LAYER met3 ;
        RECT 396.000 68.040 400.000 68.640 ;
    END
  END tl_o[23]
  PIN tl_o[24]
    DIRECTION OUTPUT ;
    USE SIGNAL ;
    ANTENNADIFFAREA 0.445500 ;
    PORT
      LAYER met3 ;
        RECT 396.000 132.640 400.000 133.240 ;
    END
  END tl_o[24]
  PIN tl_o[25]
    DIRECTION OUTPUT ;
    USE SIGNAL ;
    ANTENNADIFFAREA 0.445500 ;
    PORT
      LAYER met3 ;
        RECT 396.000 47.640 400.000 48.240 ;
    END
  END tl_o[25]
  PIN tl_o[26]
    DIRECTION OUTPUT ;
    USE SIGNAL ;
    ANTENNADIFFAREA 0.445500 ;
    PORT
      LAYER met3 ;
        RECT 396.000 54.440 400.000 55.040 ;
    END
  END tl_o[26]
  PIN tl_o[27]
    DIRECTION OUTPUT ;
    USE SIGNAL ;
    ANTENNADIFFAREA 0.445500 ;
    PORT
      LAYER met3 ;
        RECT 396.000 146.240 400.000 146.840 ;
    END
  END tl_o[27]
  PIN tl_o[28]
    DIRECTION OUTPUT ;
    USE SIGNAL ;
    ANTENNADIFFAREA 0.445500 ;
    PORT
      LAYER met3 ;
        RECT 396.000 153.040 400.000 153.640 ;
    END
  END tl_o[28]
  PIN tl_o[29]
    DIRECTION OUTPUT ;
    USE SIGNAL ;
    ANTENNADIFFAREA 0.445500 ;
    PORT
      LAYER met3 ;
        RECT 396.000 30.640 400.000 31.240 ;
    END
  END tl_o[29]
  PIN tl_o[2]
    DIRECTION OUTPUT ;
    USE SIGNAL ;
    ANTENNADIFFAREA 0.445500 ;
    PORT
      LAYER met3 ;
        RECT 396.000 200.640 400.000 201.240 ;
    END
  END tl_o[2]
  PIN tl_o[30]
    DIRECTION OUTPUT ;
    USE SIGNAL ;
    ANTENNADIFFAREA 0.445500 ;
    PORT
      LAYER met3 ;
        RECT 396.000 149.640 400.000 150.240 ;
    END
  END tl_o[30]
  PIN tl_o[31]
    DIRECTION OUTPUT ;
    USE SIGNAL ;
    ANTENNADIFFAREA 0.445500 ;
    PORT
      LAYER met3 ;
        RECT 396.000 336.640 400.000 337.240 ;
    END
  END tl_o[31]
  PIN tl_o[32]
    DIRECTION OUTPUT ;
    USE SIGNAL ;
    ANTENNADIFFAREA 0.445500 ;
    PORT
      LAYER met3 ;
        RECT 396.000 244.840 400.000 245.440 ;
    END
  END tl_o[32]
  PIN tl_o[33]
    DIRECTION OUTPUT ;
    USE SIGNAL ;
    ANTENNADIFFAREA 0.445500 ;
    PORT
      LAYER met3 ;
        RECT 396.000 275.440 400.000 276.040 ;
    END
  END tl_o[33]
  PIN tl_o[34]
    DIRECTION OUTPUT ;
    USE SIGNAL ;
    ANTENNADIFFAREA 0.445500 ;
    PORT
      LAYER met3 ;
        RECT 396.000 268.640 400.000 269.240 ;
    END
  END tl_o[34]
  PIN tl_o[35]
    DIRECTION OUTPUT ;
    USE SIGNAL ;
    ANTENNADIFFAREA 0.445500 ;
    PORT
      LAYER met3 ;
        RECT 396.000 350.240 400.000 350.840 ;
    END
  END tl_o[35]
  PIN tl_o[36]
    DIRECTION OUTPUT ;
    USE SIGNAL ;
    ANTENNADIFFAREA 0.445500 ;
    PORT
      LAYER met3 ;
        RECT 396.000 340.040 400.000 340.640 ;
    END
  END tl_o[36]
  PIN tl_o[37]
    DIRECTION OUTPUT ;
    USE SIGNAL ;
    ANTENNADIFFAREA 0.445500 ;
    PORT
      LAYER met3 ;
        RECT 396.000 309.440 400.000 310.040 ;
    END
  END tl_o[37]
  PIN tl_o[38]
    DIRECTION OUTPUT ;
    USE SIGNAL ;
    ANTENNADIFFAREA 0.445500 ;
    PORT
      LAYER met3 ;
        RECT 396.000 306.040 400.000 306.640 ;
    END
  END tl_o[38]
  PIN tl_o[39]
    DIRECTION OUTPUT ;
    USE SIGNAL ;
    ANTENNADIFFAREA 0.445500 ;
    PORT
      LAYER met3 ;
        RECT 396.000 302.640 400.000 303.240 ;
    END
  END tl_o[39]
  PIN tl_o[3]
    DIRECTION OUTPUT ;
    USE SIGNAL ;
    ANTENNADIFFAREA 0.445500 ;
    PORT
      LAYER met3 ;
        RECT 396.000 353.640 400.000 354.240 ;
    END
  END tl_o[3]
  PIN tl_o[40]
    DIRECTION OUTPUT ;
    USE SIGNAL ;
    ANTENNADIFFAREA 0.445500 ;
    PORT
      LAYER met3 ;
        RECT 396.000 343.440 400.000 344.040 ;
    END
  END tl_o[40]
  PIN tl_o[41]
    DIRECTION OUTPUT ;
    USE SIGNAL ;
    ANTENNADIFFAREA 0.445500 ;
    PORT
      LAYER met3 ;
        RECT 396.000 299.240 400.000 299.840 ;
    END
  END tl_o[41]
  PIN tl_o[42]
    DIRECTION OUTPUT ;
    USE SIGNAL ;
    ANTENNADIFFAREA 0.445500 ;
    PORT
      LAYER met3 ;
        RECT 396.000 292.440 400.000 293.040 ;
    END
  END tl_o[42]
  PIN tl_o[43]
    DIRECTION OUTPUT ;
    USE SIGNAL ;
    ANTENNADIFFAREA 0.445500 ;
    PORT
      LAYER met3 ;
        RECT 396.000 323.040 400.000 323.640 ;
    END
  END tl_o[43]
  PIN tl_o[44]
    DIRECTION OUTPUT ;
    USE SIGNAL ;
    ANTENNADIFFAREA 0.445500 ;
    PORT
      LAYER met3 ;
        RECT 396.000 261.840 400.000 262.440 ;
    END
  END tl_o[44]
  PIN tl_o[45]
    DIRECTION OUTPUT ;
    USE SIGNAL ;
    ANTENNADIFFAREA 0.445500 ;
    PORT
      LAYER met3 ;
        RECT 396.000 333.240 400.000 333.840 ;
    END
  END tl_o[45]
  PIN tl_o[46]
    DIRECTION OUTPUT ;
    USE SIGNAL ;
    ANTENNADIFFAREA 0.445500 ;
    PORT
      LAYER met3 ;
        RECT 396.000 251.640 400.000 252.240 ;
    END
  END tl_o[46]
  PIN tl_o[47]
    DIRECTION OUTPUT ;
    USE SIGNAL ;
    ANTENNADIFFAREA 0.445500 ;
    PORT
      LAYER met3 ;
        RECT 396.000 238.040 400.000 238.640 ;
    END
  END tl_o[47]
  PIN tl_o[48]
    DIRECTION OUTPUT ;
    USE SIGNAL ;
    PORT
      LAYER met2 ;
        RECT 128.890 0.000 129.170 4.000 ;
    END
  END tl_o[48]
  PIN tl_o[49]
    DIRECTION OUTPUT ;
    USE SIGNAL ;
    ANTENNADIFFAREA 0.445500 ;
    PORT
      LAYER met3 ;
        RECT 396.000 108.840 400.000 109.440 ;
    END
  END tl_o[49]
  PIN tl_o[4]
    DIRECTION OUTPUT ;
    USE SIGNAL ;
    ANTENNADIFFAREA 0.445500 ;
    PORT
      LAYER met3 ;
        RECT 396.000 231.240 400.000 231.840 ;
    END
  END tl_o[4]
  PIN tl_o[50]
    DIRECTION OUTPUT ;
    USE SIGNAL ;
    ANTENNADIFFAREA 0.445500 ;
    PORT
      LAYER met2 ;
        RECT 99.910 0.000 100.190 4.000 ;
    END
  END tl_o[50]
  PIN tl_o[51]
    DIRECTION OUTPUT ;
    USE SIGNAL ;
    ANTENNADIFFAREA 0.445500 ;
    PORT
      LAYER met3 ;
        RECT 0.000 98.640 4.000 99.240 ;
    END
  END tl_o[51]
  PIN tl_o[52]
    DIRECTION OUTPUT ;
    USE SIGNAL ;
    ANTENNADIFFAREA 0.445500 ;
    PORT
      LAYER met3 ;
        RECT 0.000 95.240 4.000 95.840 ;
    END
  END tl_o[52]
  PIN tl_o[53]
    DIRECTION OUTPUT ;
    USE SIGNAL ;
    ANTENNADIFFAREA 0.445500 ;
    PORT
      LAYER met3 ;
        RECT 396.000 88.440 400.000 89.040 ;
    END
  END tl_o[53]
  PIN tl_o[54]
    DIRECTION OUTPUT ;
    USE SIGNAL ;
    ANTENNADIFFAREA 0.445500 ;
    PORT
      LAYER met3 ;
        RECT 396.000 115.640 400.000 116.240 ;
    END
  END tl_o[54]
  PIN tl_o[55]
    DIRECTION OUTPUT ;
    USE SIGNAL ;
    ANTENNADIFFAREA 0.445500 ;
    PORT
      LAYER met3 ;
        RECT 0.000 108.840 4.000 109.440 ;
    END
  END tl_o[55]
  PIN tl_o[56]
    DIRECTION OUTPUT ;
    USE SIGNAL ;
    ANTENNADIFFAREA 0.445500 ;
    PORT
      LAYER met3 ;
        RECT 396.000 119.040 400.000 119.640 ;
    END
  END tl_o[56]
  PIN tl_o[57]
    DIRECTION OUTPUT ;
    USE SIGNAL ;
    ANTENNADIFFAREA 0.445500 ;
    PORT
      LAYER met2 ;
        RECT 293.110 0.000 293.390 4.000 ;
    END
  END tl_o[57]
  PIN tl_o[58]
    DIRECTION OUTPUT ;
    USE SIGNAL ;
    ANTENNADIFFAREA 0.445500 ;
    PORT
      LAYER met2 ;
        RECT 283.450 0.000 283.730 4.000 ;
    END
  END tl_o[58]
  PIN tl_o[59]
    DIRECTION OUTPUT ;
    USE SIGNAL ;
    PORT
      LAYER met3 ;
        RECT 396.000 289.040 400.000 289.640 ;
    END
  END tl_o[59]
  PIN tl_o[5]
    DIRECTION OUTPUT ;
    USE SIGNAL ;
    ANTENNADIFFAREA 0.445500 ;
    PORT
      LAYER met3 ;
        RECT 396.000 272.040 400.000 272.640 ;
    END
  END tl_o[5]
  PIN tl_o[60]
    DIRECTION OUTPUT ;
    USE SIGNAL ;
    PORT
      LAYER met2 ;
        RECT 309.210 0.000 309.490 4.000 ;
    END
  END tl_o[60]
  PIN tl_o[61]
    DIRECTION OUTPUT ;
    USE SIGNAL ;
    PORT
      LAYER met3 ;
        RECT 396.000 360.440 400.000 361.040 ;
    END
  END tl_o[61]
  PIN tl_o[62]
    DIRECTION OUTPUT ;
    USE SIGNAL ;
    ANTENNADIFFAREA 0.445500 ;
    PORT
      LAYER met3 ;
        RECT 396.000 112.240 400.000 112.840 ;
    END
  END tl_o[62]
  PIN tl_o[63]
    DIRECTION OUTPUT ;
    USE SIGNAL ;
    PORT
      LAYER met3 ;
        RECT 396.000 159.840 400.000 160.440 ;
    END
  END tl_o[63]
  PIN tl_o[64]
    DIRECTION OUTPUT ;
    USE SIGNAL ;
    PORT
      LAYER met2 ;
        RECT 154.650 396.000 154.930 400.000 ;
    END
  END tl_o[64]
  PIN tl_o[65]
    DIRECTION OUTPUT ;
    USE SIGNAL ;
    ANTENNADIFFAREA 0.445500 ;
    PORT
      LAYER met3 ;
        RECT 396.000 234.640 400.000 235.240 ;
    END
  END tl_o[65]
  PIN tl_o[6]
    DIRECTION OUTPUT ;
    USE SIGNAL ;
    ANTENNADIFFAREA 0.445500 ;
    PORT
      LAYER met3 ;
        RECT 396.000 217.640 400.000 218.240 ;
    END
  END tl_o[6]
  PIN tl_o[7]
    DIRECTION OUTPUT ;
    USE SIGNAL ;
    ANTENNADIFFAREA 0.445500 ;
    PORT
      LAYER met3 ;
        RECT 396.000 214.240 400.000 214.840 ;
    END
  END tl_o[7]
  PIN tl_o[8]
    DIRECTION OUTPUT ;
    USE SIGNAL ;
    ANTENNADIFFAREA 0.445500 ;
    PORT
      LAYER met3 ;
        RECT 396.000 227.840 400.000 228.440 ;
    END
  END tl_o[8]
  PIN tl_o[9]
    DIRECTION OUTPUT ;
    USE SIGNAL ;
    ANTENNADIFFAREA 0.445500 ;
    PORT
      LAYER met3 ;
        RECT 396.000 105.440 400.000 106.040 ;
    END
  END tl_o[9]
  OBS
      LAYER nwell ;
        RECT 5.330 10.760 394.410 389.150 ;
      LAYER li1 ;
        RECT 5.520 10.795 394.220 389.045 ;
      LAYER met1 ;
        RECT 5.520 10.640 395.530 389.200 ;
      LAYER met2 ;
        RECT 5.610 395.720 154.370 396.000 ;
        RECT 155.210 395.720 157.590 396.000 ;
        RECT 158.430 395.720 170.470 396.000 ;
        RECT 171.310 395.720 173.690 396.000 ;
        RECT 174.530 395.720 180.130 396.000 ;
        RECT 180.970 395.720 183.350 396.000 ;
        RECT 184.190 395.720 241.310 396.000 ;
        RECT 242.150 395.720 250.970 396.000 ;
        RECT 251.810 395.720 254.190 396.000 ;
        RECT 255.030 395.720 257.410 396.000 ;
        RECT 258.250 395.720 260.630 396.000 ;
        RECT 261.470 395.720 263.850 396.000 ;
        RECT 264.690 395.720 267.070 396.000 ;
        RECT 267.910 395.720 270.290 396.000 ;
        RECT 271.130 395.720 273.510 396.000 ;
        RECT 274.350 395.720 276.730 396.000 ;
        RECT 277.570 395.720 279.950 396.000 ;
        RECT 280.790 395.720 283.170 396.000 ;
        RECT 284.010 395.720 286.390 396.000 ;
        RECT 287.230 395.720 289.610 396.000 ;
        RECT 290.450 395.720 299.270 396.000 ;
        RECT 300.110 395.720 395.510 396.000 ;
        RECT 5.610 4.280 395.510 395.720 ;
        RECT 5.610 4.000 6.250 4.280 ;
        RECT 7.090 4.000 9.470 4.280 ;
        RECT 10.310 4.000 12.690 4.280 ;
        RECT 13.530 4.000 15.910 4.280 ;
        RECT 16.750 4.000 19.130 4.280 ;
        RECT 19.970 4.000 22.350 4.280 ;
        RECT 23.190 4.000 25.570 4.280 ;
        RECT 26.410 4.000 28.790 4.280 ;
        RECT 29.630 4.000 32.010 4.280 ;
        RECT 32.850 4.000 35.230 4.280 ;
        RECT 36.070 4.000 38.450 4.280 ;
        RECT 39.290 4.000 41.670 4.280 ;
        RECT 42.510 4.000 44.890 4.280 ;
        RECT 45.730 4.000 48.110 4.280 ;
        RECT 48.950 4.000 51.330 4.280 ;
        RECT 52.170 4.000 54.550 4.280 ;
        RECT 55.390 4.000 57.770 4.280 ;
        RECT 58.610 4.000 60.990 4.280 ;
        RECT 61.830 4.000 64.210 4.280 ;
        RECT 65.050 4.000 67.430 4.280 ;
        RECT 68.270 4.000 70.650 4.280 ;
        RECT 71.490 4.000 73.870 4.280 ;
        RECT 74.710 4.000 77.090 4.280 ;
        RECT 77.930 4.000 80.310 4.280 ;
        RECT 81.150 4.000 83.530 4.280 ;
        RECT 84.370 4.000 86.750 4.280 ;
        RECT 87.590 4.000 89.970 4.280 ;
        RECT 90.810 4.000 93.190 4.280 ;
        RECT 94.030 4.000 96.410 4.280 ;
        RECT 97.250 4.000 99.630 4.280 ;
        RECT 100.470 4.000 102.850 4.280 ;
        RECT 103.690 4.000 106.070 4.280 ;
        RECT 106.910 4.000 109.290 4.280 ;
        RECT 110.130 4.000 112.510 4.280 ;
        RECT 113.350 4.000 115.730 4.280 ;
        RECT 116.570 4.000 118.950 4.280 ;
        RECT 119.790 4.000 122.170 4.280 ;
        RECT 123.010 4.000 125.390 4.280 ;
        RECT 126.230 4.000 128.610 4.280 ;
        RECT 129.450 4.000 131.830 4.280 ;
        RECT 132.670 4.000 135.050 4.280 ;
        RECT 135.890 4.000 138.270 4.280 ;
        RECT 139.110 4.000 141.490 4.280 ;
        RECT 142.330 4.000 144.710 4.280 ;
        RECT 145.550 4.000 147.930 4.280 ;
        RECT 148.770 4.000 151.150 4.280 ;
        RECT 151.990 4.000 154.370 4.280 ;
        RECT 155.210 4.000 157.590 4.280 ;
        RECT 158.430 4.000 160.810 4.280 ;
        RECT 161.650 4.000 164.030 4.280 ;
        RECT 164.870 4.000 167.250 4.280 ;
        RECT 168.090 4.000 170.470 4.280 ;
        RECT 171.310 4.000 173.690 4.280 ;
        RECT 174.530 4.000 180.130 4.280 ;
        RECT 180.970 4.000 183.350 4.280 ;
        RECT 184.190 4.000 186.570 4.280 ;
        RECT 187.410 4.000 189.790 4.280 ;
        RECT 190.630 4.000 196.230 4.280 ;
        RECT 197.070 4.000 218.770 4.280 ;
        RECT 219.610 4.000 221.990 4.280 ;
        RECT 222.830 4.000 225.210 4.280 ;
        RECT 226.050 4.000 231.650 4.280 ;
        RECT 232.490 4.000 267.070 4.280 ;
        RECT 267.910 4.000 270.290 4.280 ;
        RECT 271.130 4.000 273.510 4.280 ;
        RECT 274.350 4.000 276.730 4.280 ;
        RECT 277.570 4.000 279.950 4.280 ;
        RECT 280.790 4.000 283.170 4.280 ;
        RECT 284.010 4.000 286.390 4.280 ;
        RECT 287.230 4.000 289.610 4.280 ;
        RECT 290.450 4.000 292.830 4.280 ;
        RECT 293.670 4.000 296.050 4.280 ;
        RECT 296.890 4.000 308.930 4.280 ;
        RECT 309.770 4.000 395.510 4.280 ;
      LAYER met3 ;
        RECT 4.000 361.440 396.000 389.125 ;
        RECT 4.000 360.040 395.600 361.440 ;
        RECT 4.000 358.040 396.000 360.040 ;
        RECT 4.000 356.640 395.600 358.040 ;
        RECT 4.000 354.640 396.000 356.640 ;
        RECT 4.000 353.240 395.600 354.640 ;
        RECT 4.000 351.240 396.000 353.240 ;
        RECT 4.000 349.840 395.600 351.240 ;
        RECT 4.000 347.840 396.000 349.840 ;
        RECT 4.000 346.440 395.600 347.840 ;
        RECT 4.000 344.440 396.000 346.440 ;
        RECT 4.000 343.040 395.600 344.440 ;
        RECT 4.000 341.040 396.000 343.040 ;
        RECT 4.000 339.640 395.600 341.040 ;
        RECT 4.000 337.640 396.000 339.640 ;
        RECT 4.000 336.240 395.600 337.640 ;
        RECT 4.000 334.240 396.000 336.240 ;
        RECT 4.000 332.840 395.600 334.240 ;
        RECT 4.000 330.840 396.000 332.840 ;
        RECT 4.000 329.440 395.600 330.840 ;
        RECT 4.000 327.440 396.000 329.440 ;
        RECT 4.000 326.040 395.600 327.440 ;
        RECT 4.000 324.040 396.000 326.040 ;
        RECT 4.000 322.640 395.600 324.040 ;
        RECT 4.000 320.640 396.000 322.640 ;
        RECT 4.000 319.240 395.600 320.640 ;
        RECT 4.000 317.240 396.000 319.240 ;
        RECT 4.000 315.840 395.600 317.240 ;
        RECT 4.000 313.840 396.000 315.840 ;
        RECT 4.000 312.440 395.600 313.840 ;
        RECT 4.000 310.440 396.000 312.440 ;
        RECT 4.000 309.040 395.600 310.440 ;
        RECT 4.000 307.040 396.000 309.040 ;
        RECT 4.000 305.640 395.600 307.040 ;
        RECT 4.000 303.640 396.000 305.640 ;
        RECT 4.000 302.240 395.600 303.640 ;
        RECT 4.000 300.240 396.000 302.240 ;
        RECT 4.000 298.840 395.600 300.240 ;
        RECT 4.000 296.840 396.000 298.840 ;
        RECT 4.000 295.440 395.600 296.840 ;
        RECT 4.000 293.440 396.000 295.440 ;
        RECT 4.000 292.040 395.600 293.440 ;
        RECT 4.000 290.040 396.000 292.040 ;
        RECT 4.000 288.640 395.600 290.040 ;
        RECT 4.000 286.640 396.000 288.640 ;
        RECT 4.000 285.240 395.600 286.640 ;
        RECT 4.000 283.240 396.000 285.240 ;
        RECT 4.000 281.840 395.600 283.240 ;
        RECT 4.000 279.840 396.000 281.840 ;
        RECT 4.000 278.440 395.600 279.840 ;
        RECT 4.000 276.440 396.000 278.440 ;
        RECT 4.000 275.040 395.600 276.440 ;
        RECT 4.000 273.040 396.000 275.040 ;
        RECT 4.000 271.640 395.600 273.040 ;
        RECT 4.000 269.640 396.000 271.640 ;
        RECT 4.000 268.240 395.600 269.640 ;
        RECT 4.000 266.240 396.000 268.240 ;
        RECT 4.000 264.840 395.600 266.240 ;
        RECT 4.000 262.840 396.000 264.840 ;
        RECT 4.000 261.440 395.600 262.840 ;
        RECT 4.000 259.440 396.000 261.440 ;
        RECT 4.000 258.040 395.600 259.440 ;
        RECT 4.000 256.040 396.000 258.040 ;
        RECT 4.000 254.640 395.600 256.040 ;
        RECT 4.000 252.640 396.000 254.640 ;
        RECT 4.000 251.240 395.600 252.640 ;
        RECT 4.000 249.240 396.000 251.240 ;
        RECT 4.000 247.840 395.600 249.240 ;
        RECT 4.000 245.840 396.000 247.840 ;
        RECT 4.000 244.440 395.600 245.840 ;
        RECT 4.000 242.440 396.000 244.440 ;
        RECT 4.000 241.040 395.600 242.440 ;
        RECT 4.000 239.040 396.000 241.040 ;
        RECT 4.000 237.640 395.600 239.040 ;
        RECT 4.000 235.640 396.000 237.640 ;
        RECT 4.000 234.240 395.600 235.640 ;
        RECT 4.000 232.240 396.000 234.240 ;
        RECT 4.000 230.840 395.600 232.240 ;
        RECT 4.000 228.840 396.000 230.840 ;
        RECT 4.000 227.440 395.600 228.840 ;
        RECT 4.000 225.440 396.000 227.440 ;
        RECT 4.000 224.040 395.600 225.440 ;
        RECT 4.000 222.040 396.000 224.040 ;
        RECT 4.000 220.640 395.600 222.040 ;
        RECT 4.000 218.640 396.000 220.640 ;
        RECT 4.000 217.240 395.600 218.640 ;
        RECT 4.000 215.240 396.000 217.240 ;
        RECT 4.400 213.840 395.600 215.240 ;
        RECT 4.000 211.840 396.000 213.840 ;
        RECT 4.000 210.440 395.600 211.840 ;
        RECT 4.000 208.440 396.000 210.440 ;
        RECT 4.400 207.040 395.600 208.440 ;
        RECT 4.000 205.040 396.000 207.040 ;
        RECT 4.400 203.640 395.600 205.040 ;
        RECT 4.000 201.640 396.000 203.640 ;
        RECT 4.400 200.240 395.600 201.640 ;
        RECT 4.000 198.240 396.000 200.240 ;
        RECT 4.000 196.840 395.600 198.240 ;
        RECT 4.000 194.840 396.000 196.840 ;
        RECT 4.000 193.440 395.600 194.840 ;
        RECT 4.000 191.440 396.000 193.440 ;
        RECT 4.000 190.040 395.600 191.440 ;
        RECT 4.000 188.040 396.000 190.040 ;
        RECT 4.000 186.640 395.600 188.040 ;
        RECT 4.000 184.640 396.000 186.640 ;
        RECT 4.000 183.240 395.600 184.640 ;
        RECT 4.000 181.240 396.000 183.240 ;
        RECT 4.000 179.840 395.600 181.240 ;
        RECT 4.000 177.840 396.000 179.840 ;
        RECT 4.000 176.440 395.600 177.840 ;
        RECT 4.000 174.440 396.000 176.440 ;
        RECT 4.000 173.040 395.600 174.440 ;
        RECT 4.000 171.040 396.000 173.040 ;
        RECT 4.000 169.640 395.600 171.040 ;
        RECT 4.000 167.640 396.000 169.640 ;
        RECT 4.000 166.240 395.600 167.640 ;
        RECT 4.000 164.240 396.000 166.240 ;
        RECT 4.000 162.840 395.600 164.240 ;
        RECT 4.000 160.840 396.000 162.840 ;
        RECT 4.000 159.440 395.600 160.840 ;
        RECT 4.000 157.440 396.000 159.440 ;
        RECT 4.000 156.040 395.600 157.440 ;
        RECT 4.000 154.040 396.000 156.040 ;
        RECT 4.000 152.640 395.600 154.040 ;
        RECT 4.000 150.640 396.000 152.640 ;
        RECT 4.000 149.240 395.600 150.640 ;
        RECT 4.000 147.240 396.000 149.240 ;
        RECT 4.000 145.840 395.600 147.240 ;
        RECT 4.000 143.840 396.000 145.840 ;
        RECT 4.000 142.440 395.600 143.840 ;
        RECT 4.000 140.440 396.000 142.440 ;
        RECT 4.000 139.040 395.600 140.440 ;
        RECT 4.000 137.040 396.000 139.040 ;
        RECT 4.000 135.640 395.600 137.040 ;
        RECT 4.000 133.640 396.000 135.640 ;
        RECT 4.000 132.240 395.600 133.640 ;
        RECT 4.000 130.240 396.000 132.240 ;
        RECT 4.000 128.840 395.600 130.240 ;
        RECT 4.000 126.840 396.000 128.840 ;
        RECT 4.000 125.440 395.600 126.840 ;
        RECT 4.000 123.440 396.000 125.440 ;
        RECT 4.000 122.040 395.600 123.440 ;
        RECT 4.000 120.040 396.000 122.040 ;
        RECT 4.000 118.640 395.600 120.040 ;
        RECT 4.000 116.640 396.000 118.640 ;
        RECT 4.000 115.240 395.600 116.640 ;
        RECT 4.000 113.240 396.000 115.240 ;
        RECT 4.400 111.840 395.600 113.240 ;
        RECT 4.000 109.840 396.000 111.840 ;
        RECT 4.400 108.440 395.600 109.840 ;
        RECT 4.000 106.440 396.000 108.440 ;
        RECT 4.400 105.040 395.600 106.440 ;
        RECT 4.000 103.040 396.000 105.040 ;
        RECT 4.400 101.640 395.600 103.040 ;
        RECT 4.000 99.640 396.000 101.640 ;
        RECT 4.400 98.240 395.600 99.640 ;
        RECT 4.000 96.240 396.000 98.240 ;
        RECT 4.400 94.840 395.600 96.240 ;
        RECT 4.000 92.840 396.000 94.840 ;
        RECT 4.400 91.440 395.600 92.840 ;
        RECT 4.000 89.440 396.000 91.440 ;
        RECT 4.000 88.040 395.600 89.440 ;
        RECT 4.000 86.040 396.000 88.040 ;
        RECT 4.000 84.640 395.600 86.040 ;
        RECT 4.000 82.640 396.000 84.640 ;
        RECT 4.000 81.240 395.600 82.640 ;
        RECT 4.000 79.240 396.000 81.240 ;
        RECT 4.000 77.840 395.600 79.240 ;
        RECT 4.000 75.840 396.000 77.840 ;
        RECT 4.000 74.440 395.600 75.840 ;
        RECT 4.000 72.440 396.000 74.440 ;
        RECT 4.000 71.040 395.600 72.440 ;
        RECT 4.000 69.040 396.000 71.040 ;
        RECT 4.000 67.640 395.600 69.040 ;
        RECT 4.000 65.640 396.000 67.640 ;
        RECT 4.000 64.240 395.600 65.640 ;
        RECT 4.000 62.240 396.000 64.240 ;
        RECT 4.000 60.840 395.600 62.240 ;
        RECT 4.000 58.840 396.000 60.840 ;
        RECT 4.000 57.440 395.600 58.840 ;
        RECT 4.000 55.440 396.000 57.440 ;
        RECT 4.000 54.040 395.600 55.440 ;
        RECT 4.000 52.040 396.000 54.040 ;
        RECT 4.000 50.640 395.600 52.040 ;
        RECT 4.000 48.640 396.000 50.640 ;
        RECT 4.000 47.240 395.600 48.640 ;
        RECT 4.000 45.240 396.000 47.240 ;
        RECT 4.000 43.840 395.600 45.240 ;
        RECT 4.000 41.840 396.000 43.840 ;
        RECT 4.000 40.440 395.600 41.840 ;
        RECT 4.000 38.440 396.000 40.440 ;
        RECT 4.000 37.040 395.600 38.440 ;
        RECT 4.000 35.040 396.000 37.040 ;
        RECT 4.000 33.640 395.600 35.040 ;
        RECT 4.000 31.640 396.000 33.640 ;
        RECT 4.000 30.240 395.600 31.640 ;
        RECT 4.000 28.240 396.000 30.240 ;
        RECT 4.000 26.840 395.600 28.240 ;
        RECT 4.000 24.840 396.000 26.840 ;
        RECT 4.000 23.440 395.600 24.840 ;
        RECT 4.000 21.440 396.000 23.440 ;
        RECT 4.000 20.040 395.600 21.440 ;
        RECT 4.000 18.040 396.000 20.040 ;
        RECT 4.000 16.640 395.600 18.040 ;
        RECT 4.000 14.640 396.000 16.640 ;
        RECT 4.000 13.240 395.600 14.640 ;
        RECT 4.000 11.240 396.000 13.240 ;
        RECT 4.000 10.375 395.600 11.240 ;
      LAYER met4 ;
        RECT 188.895 13.095 327.840 386.745 ;
        RECT 330.240 13.095 331.140 386.745 ;
        RECT 333.540 13.095 385.185 386.745 ;
  END
END rv_plic_lite
END LIBRARY

